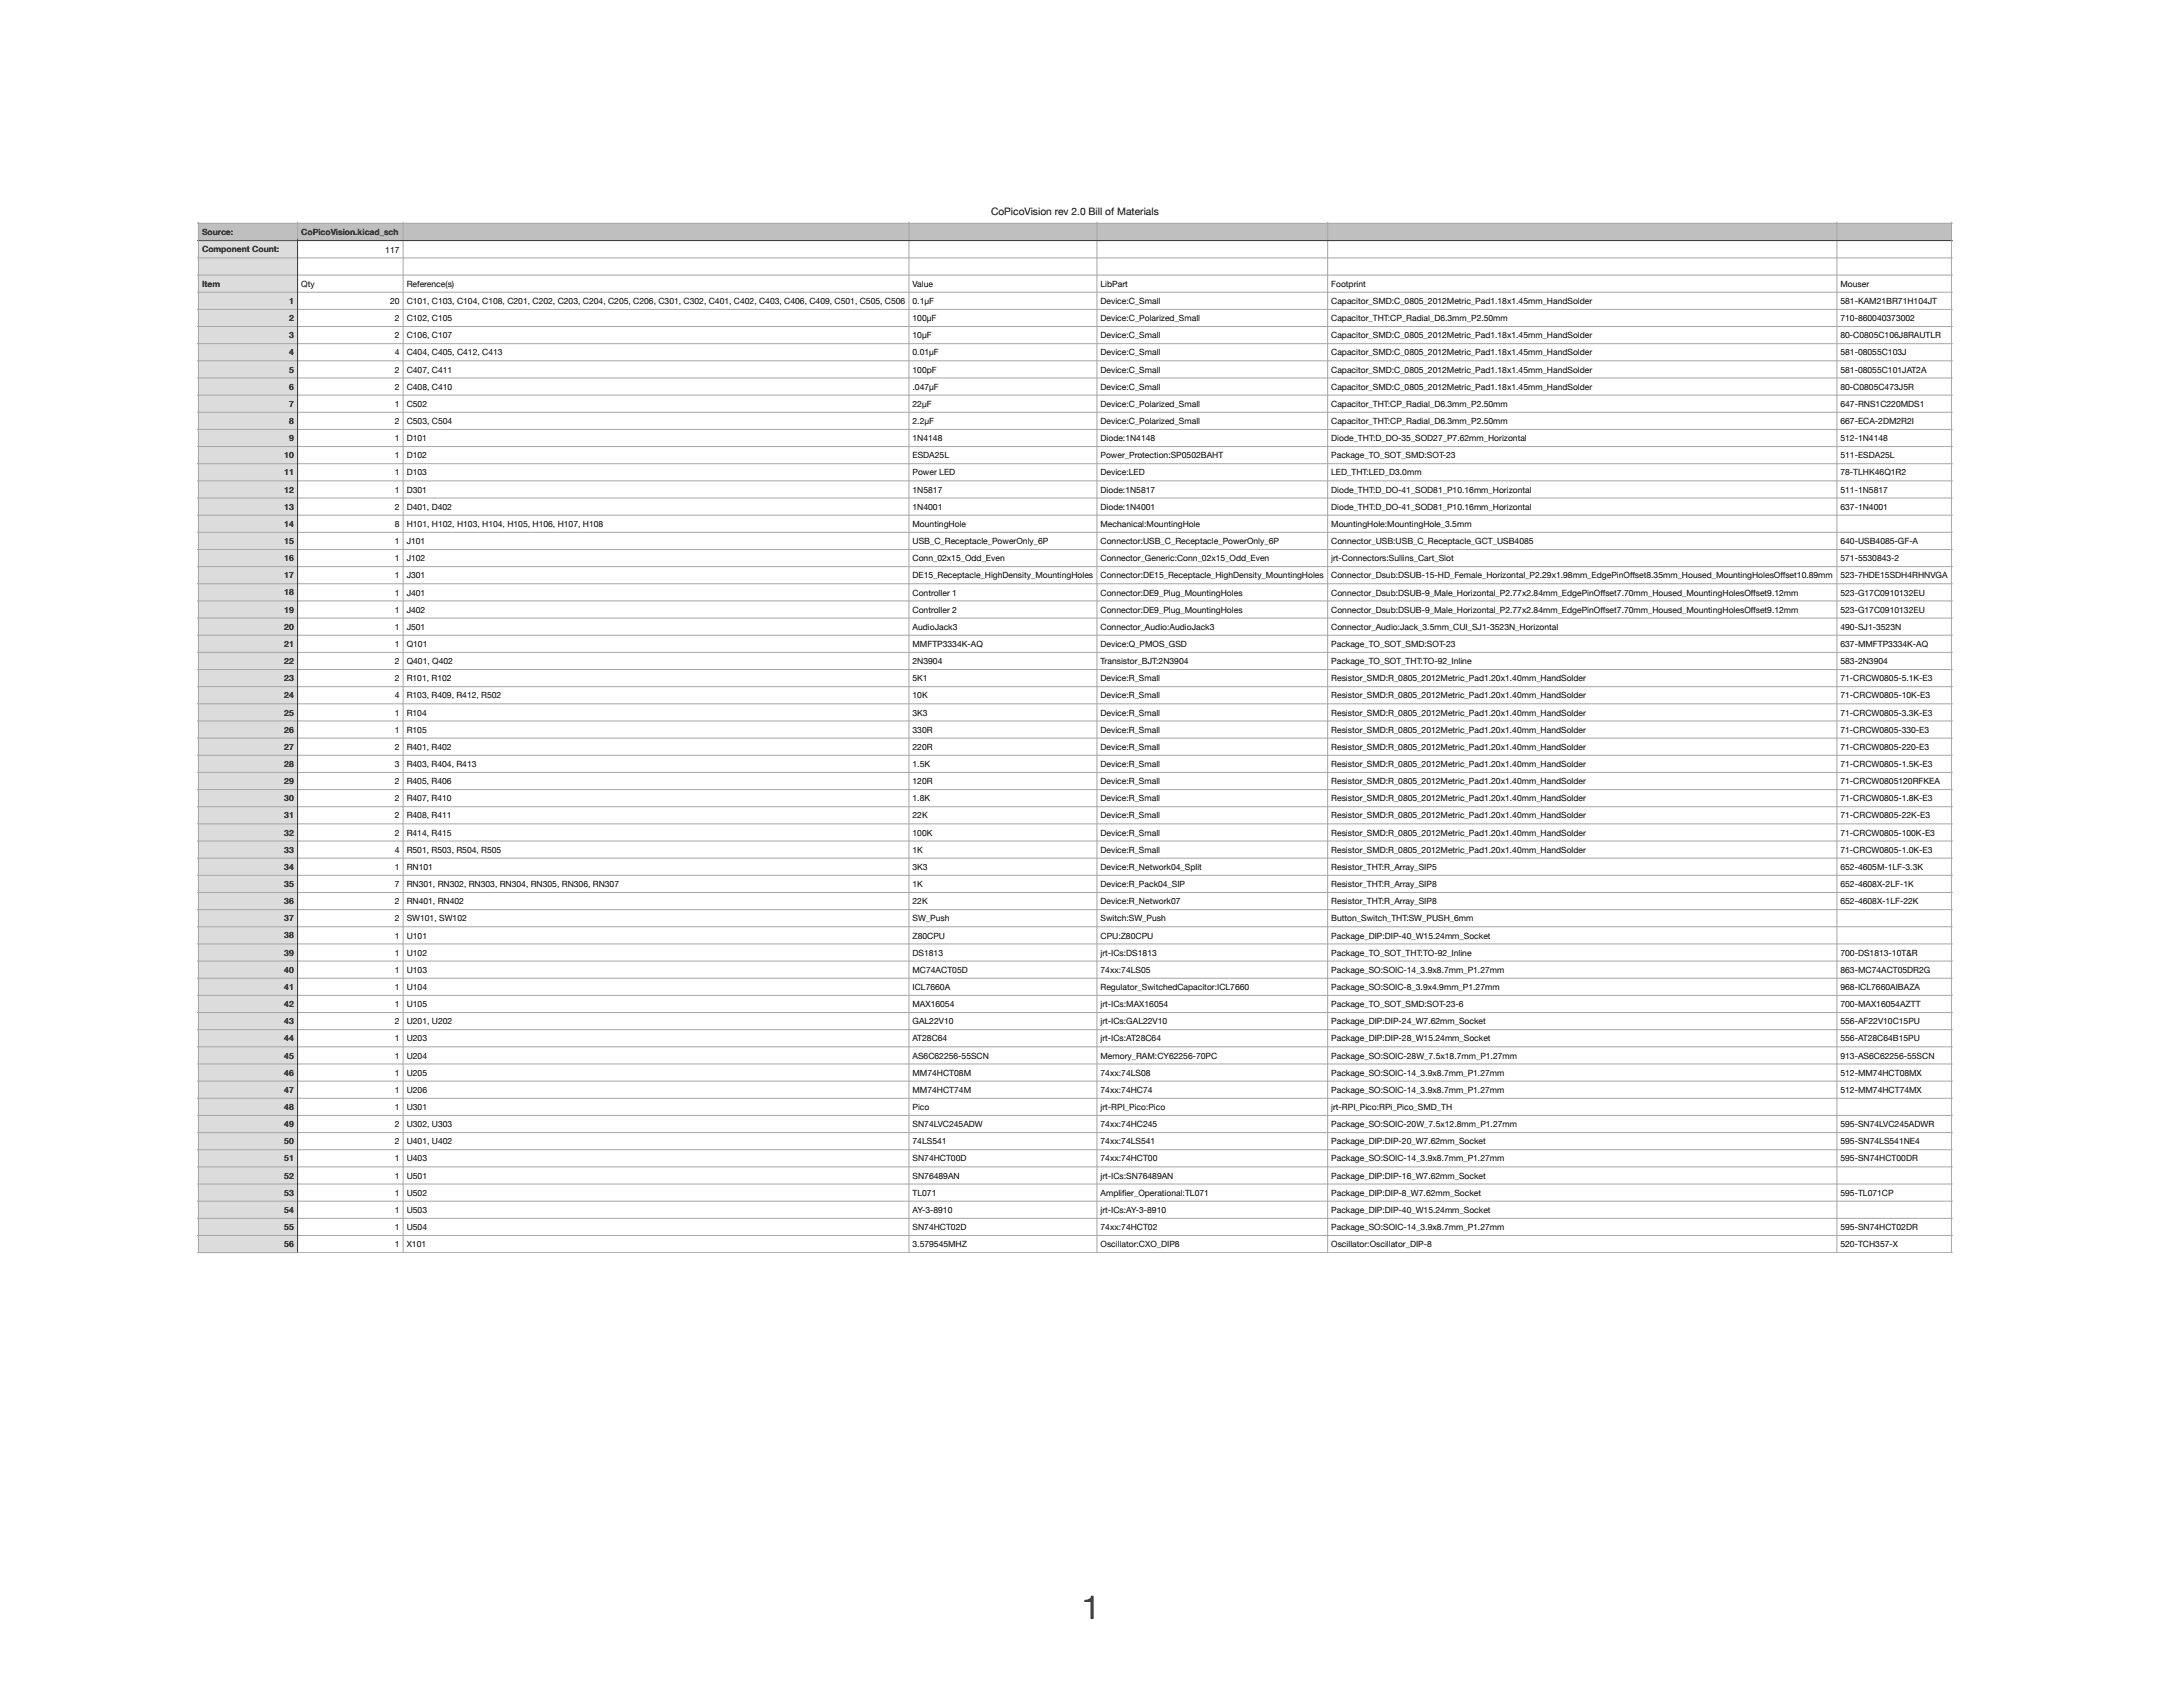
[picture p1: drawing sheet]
<svg xmlns="http://www.w3.org/2000/svg" width="279mm" height="216mm" viewBox="0 0 279 216" stroke-linecap="round" stroke-linejoin="round" font-family="sans-serif">
<defs><g id="words">
<text font-size="4.2" x="138.5" y="207.2">1</text>
<text font-size="1.3" x="126.8" y="27.5">CoPicoVision rev 2.0 Bill of Materials</text>
<g font-size="1.1">
<text x="25.9" y="30.1">Source:</text>
<text x="25.9" y="32.3">Component Count:</text>
<text x="38.5" y="30.1">CoPicoVision.kicad_sch</text>
<text x="49.3" y="32.3">117</text>
<text x="25.9" y="36.7">Item</text>
<text x="37" y="38.9">1</text>
<text x="37" y="41.1">2</text>
<text x="38.6" y="36.7">Qty</text>
<text x="49.9" y="38.9">20</text>
<text x="50.5" y="41.1">2</text>
<text x="52.1" y="36.7">Reference(s)</text>
<text x="52.1" y="38.9">C101, C103, C104, C108, C201, C202, C203, C204, C205, C206, C301, C302, C401, C402, C403, C406, C409, C501, C505, C506</text>
<text x="52.1" y="41.1">C102, C105</text>
<text x="116.8" y="36.7">Value</text>
<text x="116.8" y="38.9">0.1µF</text>
<text x="116.8" y="41.1">100µF</text>
<text x="140.9" y="36.7">LibPart</text>
<text x="140.9" y="38.9">Device:C_Small</text>
<text x="140.9" y="41.1">Device:C_Polarized_Small</text>
<text x="170.4" y="36.7">Footprint</text>
<text x="170.4" y="38.9">Capacitor_SMD:C_0805_2012Metric_Pad1.18x1.45mm_HandSolder</text>
<text x="170.4" y="41.1">Capacitor_THT:CP_Radial_D6.3mm_P2.50mm</text>
<text x="235.6" y="36.7">Mouser</text>
<text x="235.6" y="38.9">581-KAM21BR71H104JT</text>
<text x="235.6" y="41.1">710-860040373002</text>
<text x="37" y="43.3">3</text>
<text x="37" y="45.5">4</text>
<text x="37" y="47.7">5</text>
<text x="50.5" y="43.3">2</text>
<text x="50.5" y="45.5">4</text>
<text x="50.5" y="47.7">2</text>
<text x="52.1" y="43.3">C106, C107</text>
<text x="52.1" y="45.5">C404, C405, C412, C413</text>
<text x="52.1" y="47.7">C407, C411</text>
<text x="116.8" y="43.3">10µF</text>
<text x="116.8" y="45.5">0.01µF</text>
<text x="116.8" y="47.7">100pF</text>
<text x="140.9" y="43.3">Device:C_Small</text>
<text x="140.9" y="45.5">Device:C_Small</text>
<text x="140.9" y="47.7">Device:C_Small</text>
<text x="170.4" y="43.3">Capacitor_SMD:C_0805_2012Metric_Pad1.18x1.45mm_HandSolder</text>
<text x="170.4" y="45.5">Capacitor_SMD:C_0805_2012Metric_Pad1.18x1.45mm_HandSolder</text>
<text x="170.4" y="47.7">Capacitor_SMD:C_0805_2012Metric_Pad1.18x1.45mm_HandSolder</text>
<text x="235.6" y="43.3">80-C0805C106J8RAUTLR</text>
<text x="235.6" y="45.5">581-08055C103J</text>
<text x="235.6" y="47.7">581-08055C101JAT2A</text>
<text x="37" y="49.9">6</text>
<text x="37" y="52.1">7</text>
<text x="50.5" y="49.9">2</text>
<text x="50.5" y="52.1">1</text>
<text x="52.1" y="49.9">C408, C410</text>
<text x="52.1" y="52.1">C502</text>
<text x="116.8" y="49.9">.047µF</text>
<text x="116.8" y="52.1">22µF</text>
<text x="140.9" y="49.9">Device:C_Small</text>
<text x="140.9" y="52.1">Device:C_Polarized_Small</text>
<text x="170.4" y="49.9">Capacitor_SMD:C_0805_2012Metric_Pad1.18x1.45mm_HandSolder</text>
<text x="170.4" y="52.1">Capacitor_THT:CP_Radial_D6.3mm_P2.50mm</text>
<text x="235.6" y="49.9">80-C0805C473J5R</text>
<text x="235.6" y="52.1">647-RNS1C220MDS1</text>
<text x="36.4" y="58.7">10</text>
<text x="37" y="54.3">8</text>
<text x="37" y="56.5">9</text>
<text x="50.5" y="54.3">2</text>
<text x="50.5" y="56.5">1</text>
<text x="50.5" y="58.7">1</text>
<text x="52.1" y="54.3">C503, C504</text>
<text x="52.1" y="56.5">D101</text>
<text x="52.1" y="58.7">D102</text>
<text x="116.8" y="54.3">2.2µF</text>
<text x="116.8" y="56.5">1N4148</text>
<text x="116.8" y="58.7">ESDA25L</text>
<text x="140.9" y="54.3">Device:C_Polarized_Small</text>
<text x="140.9" y="56.5">Diode:1N4148</text>
<text x="140.9" y="58.7">Power_Protection:SP0502BAHT</text>
<text x="170.4" y="54.3">Capacitor_THT:CP_Radial_D6.3mm_P2.50mm</text>
<text x="170.4" y="56.5">Diode_THT:D_DO-35_SOD27_P7.62mm_Horizontal</text>
<text x="170.4" y="58.7">Package_TO_SOT_SMD:SOT-23</text>
<text x="235.6" y="54.3">667-ECA-2DM2R2I</text>
<text x="235.6" y="56.5">512-1N4148</text>
<text x="235.6" y="58.7">511-ESDA25L</text>
<text x="36.4" y="60.8">11</text>
<text x="36.4" y="63">12</text>
<text x="36.4" y="65.2">13</text>
<text x="50.5" y="60.9">1</text>
<text x="50.5" y="63">1</text>
<text x="50.5" y="65.2">2</text>
<text x="52.1" y="60.9">D103</text>
<text x="52.1" y="63">D301</text>
<text x="52.1" y="65.2">D401, D402</text>
<text x="116.8" y="60.9">Power LED</text>
<text x="116.8" y="63">1N5817</text>
<text x="116.8" y="65.2">1N4001</text>
<text x="140.9" y="60.9">Device:LED</text>
<text x="140.9" y="63">Diode:1N5817</text>
<text x="140.9" y="65.2">Diode:1N4001</text>
<text x="170.4" y="60.9">LED_THT:LED_D3.0mm</text>
<text x="170.4" y="63">Diode_THT:D_DO-41_SOD81_P10.16mm_Horizontal</text>
<text x="170.4" y="65.2">Diode_THT:D_DO-41_SOD81_P10.16mm_Horizontal</text>
<text x="235.6" y="60.9">78-TLHK46Q1R2</text>
<text x="235.6" y="63">511-1N5817</text>
<text x="235.6" y="65.2">637-1N4001</text>
<text x="36.4" y="67.4">14</text>
<text x="36.4" y="69.6">15</text>
<text x="36.4" y="71.8">16</text>
<text x="50.5" y="67.4">8</text>
<text x="50.5" y="69.6">1</text>
<text x="50.5" y="71.8">1</text>
<text x="52.1" y="67.4">H101, H102, H103, H104, H105, H106, H107, H108</text>
<text x="52.1" y="69.6">J101</text>
<text x="52.1" y="71.8">J102</text>
<text x="116.8" y="67.4">MountingHole</text>
<text x="116.8" y="69.6">USB_C_Receptacle_PowerOnly_6P</text>
<text x="116.8" y="71.8">Conn_02x15_Odd_Even</text>
<text x="140.9" y="67.4">Mechanical:MountingHole</text>
<text x="140.9" y="69.6">Connector:USB_C_Receptacle_PowerOnly_6P</text>
<text x="140.9" y="71.8">Connector_Generic:Conn_02x15_Odd_Even</text>
<text x="170.4" y="67.4">MountingHole:MountingHole_3.5mm</text>
<text x="170.4" y="69.6">Connector_USB:USB_C_Receptacle_GCT_USB4085</text>
<text x="170.4" y="71.8">jrt-Connectors:Sullins_Cart_Slot</text>
<text x="235.6" y="69.6">640-USB4085-GF-A</text>
<text x="235.6" y="71.8">571-5530843-2</text>
<text x="36.4" y="74">17</text>
<text x="36.4" y="76.2">18</text>
<text x="50.5" y="74">1</text>
<text x="50.5" y="76.2">1</text>
<text x="52.1" y="74">J301</text>
<text x="52.1" y="76.2">J401</text>
<text x="116.8" y="74">DE15_Receptacle_HighDensity_MountingHoles</text>
<text x="116.8" y="76.2">Controller 1</text>
<text x="140.9" y="74">Connector:DE15_Receptacle_HighDensity_MountingHoles</text>
<text x="140.9" y="76.2">Connector:DE9_Plug_MountingHoles</text>
<text x="170.4" y="74">Connector_Dsub:DSUB-15-HD_Female_Horizontal_P2.29x1.98mm_EdgePinOff set8.35mm_Housed_MountingHolesOff set10.89mm</text>
<text x="170.4" y="76.2">Connector_Dsub:DSUB-9_Male_Horizontal_P2.77x2.84mm_EdgePinOff set7.70mm_Housed_MountingHolesOff set9.12mm</text>
<text x="235.6" y="74">523-7HDE15SDH4RHNVGA</text>
<text x="235.6" y="76.2">523-G17C0910132EU</text>
<text x="36.4" y="78.4">19</text>
<text x="36.4" y="80.6">20</text>
<text x="36.4" y="82.8">21</text>
<text x="50.5" y="78.4">1</text>
<text x="50.5" y="80.6">1</text>
<text x="50.5" y="82.8">1</text>
<text x="52.1" y="78.4">J402</text>
<text x="52.1" y="80.6">J501</text>
<text x="52.1" y="82.8">Q101</text>
<text x="116.8" y="78.4">Controller 2</text>
<text x="116.8" y="80.6">AudioJack3</text>
<text x="116.8" y="82.8">MMFTP3334K-AQ</text>
<text x="140.9" y="78.4">Connector:DE9_Plug_MountingHoles</text>
<text x="140.9" y="80.6">Connector_Audio:AudioJack3</text>
<text x="140.9" y="82.8">Device:Q_PMOS_GSD</text>
<text x="170.4" y="78.4">Connector_Dsub:DSUB-9_Male_Horizontal_P2.77x2.84mm_EdgePinOff set7.70mm_Housed_MountingHolesOff set9.12mm</text>
<text x="170.4" y="80.6">Connector_Audio:Jack_3.5mm_CUI_SJ1-3523N_Horizontal</text>
<text x="170.4" y="82.8">Package_TO_SOT_SMD:SOT-23</text>
<text x="235.6" y="78.4">523-G17C0910132EU</text>
<text x="235.6" y="80.6">490-SJ1-3523N</text>
<text x="235.6" y="82.8">637-MMFTP3334K-AQ</text>
<text x="36.4" y="85">22</text>
<text x="36.4" y="87.2">23</text>
<text x="36.4" y="89.4">24</text>
<text x="50.5" y="85">2</text>
<text x="50.5" y="87.2">2</text>
<text x="50.5" y="89.4">4</text>
<text x="52.1" y="85">Q401, Q402</text>
<text x="52.1" y="87.2">R101, R102</text>
<text x="52.1" y="89.4">R103, R409, R412, R502</text>
<text x="116.8" y="85">2N3904</text>
<text x="116.8" y="87.2">5K1</text>
<text x="116.8" y="89.4">10K</text>
<text x="140.9" y="85">Transistor_BJT:2N3904</text>
<text x="140.9" y="87.2">Device:R_Small</text>
<text x="140.9" y="89.4">Device:R_Small</text>
<text x="170.4" y="85">Package_TO_SOT_THT:TO-92_Inline</text>
<text x="170.4" y="87.2">Resistor_SMD:R_0805_2012Metric_Pad1.20x1.40mm_HandSolder</text>
<text x="170.4" y="89.4">Resistor_SMD:R_0805_2012Metric_Pad1.20x1.40mm_HandSolder</text>
<text x="235.6" y="85">583-2N3904</text>
<text x="235.6" y="87.2">71-CRCW0805-5.1K-E3</text>
<text x="235.6" y="89.4">71-CRCW0805-10K-E3</text>
<text x="36.4" y="91.6">25</text>
<text x="36.4" y="93.8">26</text>
<text x="36.4" y="96">27</text>
<text x="50.5" y="91.6">1</text>
<text x="50.5" y="93.8">1</text>
<text x="50.5" y="96">2</text>
<text x="52.1" y="91.6">R104</text>
<text x="52.1" y="93.8">R105</text>
<text x="52.1" y="96">R401, R402</text>
<text x="116.8" y="91.6">3K3</text>
<text x="116.8" y="93.8">330R</text>
<text x="116.8" y="96">220R</text>
<text x="140.9" y="91.6">Device:R_Small</text>
<text x="140.9" y="93.8">Device:R_Small</text>
<text x="140.9" y="96">Device:R_Small</text>
<text x="170.4" y="91.6">Resistor_SMD:R_0805_2012Metric_Pad1.20x1.40mm_HandSolder</text>
<text x="170.4" y="93.8">Resistor_SMD:R_0805_2012Metric_Pad1.20x1.40mm_HandSolder</text>
<text x="170.4" y="96">Resistor_SMD:R_0805_2012Metric_Pad1.20x1.40mm_HandSolder</text>
<text x="235.6" y="91.6">71-CRCW0805-3.3K-E3</text>
<text x="235.6" y="93.8">71-CRCW0805-330-E3</text>
<text x="235.6" y="96">71-CRCW0805-220-E3</text>
<text x="36.4" y="98.2">28</text>
<text x="36.4" y="100.4">29</text>
<text x="50.5" y="98.2">3</text>
<text x="50.5" y="100.4">2</text>
<text x="52.1" y="98.2">R403, R404, R413</text>
<text x="52.1" y="100.4">R405, R406</text>
<text x="116.8" y="98.2">1.5K</text>
<text x="116.8" y="100.4">120R</text>
<text x="140.9" y="98.2">Device:R_Small</text>
<text x="140.9" y="100.4">Device:R_Small</text>
<text x="170.4" y="98.2">Resistor_SMD:R_0805_2012Metric_Pad1.20x1.40mm_HandSolder</text>
<text x="170.4" y="100.4">Resistor_SMD:R_0805_2012Metric_Pad1.20x1.40mm_HandSolder</text>
<text x="235.6" y="98.2">71-CRCW0805-1.5K-E3</text>
<text x="235.6" y="100.4">71-CRCW0805120RFKEA</text>
<text x="36.4" y="102.5">30</text>
<text x="36.4" y="104.7">31</text>
<text x="36.4" y="106.9">32</text>
<text x="50.5" y="102.6">2</text>
<text x="50.5" y="104.7">2</text>
<text x="50.5" y="106.9">2</text>
<text x="52.1" y="102.6">R407, R410</text>
<text x="52.1" y="104.7">R408, R411</text>
<text x="52.1" y="106.9">R414, R415</text>
<text x="116.8" y="102.6">1.8K</text>
<text x="116.8" y="104.7">22K</text>
<text x="116.8" y="106.9">100K</text>
<text x="140.9" y="102.6">Device:R_Small</text>
<text x="140.9" y="104.7">Device:R_Small</text>
<text x="140.9" y="106.9">Device:R_Small</text>
<text x="170.4" y="102.6">Resistor_SMD:R_0805_2012Metric_Pad1.20x1.40mm_HandSolder</text>
<text x="170.4" y="104.7">Resistor_SMD:R_0805_2012Metric_Pad1.20x1.40mm_HandSolder</text>
<text x="170.4" y="106.9">Resistor_SMD:R_0805_2012Metric_Pad1.20x1.40mm_HandSolder</text>
<text x="235.6" y="102.6">71-CRCW0805-1.8K-E3</text>
<text x="235.6" y="104.7">71-CRCW0805-22K-E3</text>
<text x="235.6" y="106.9">71-CRCW0805-100K-E3</text>
<text x="36.4" y="109.1">33</text>
<text x="36.4" y="111.3">34</text>
<text x="36.4" y="113.5">35</text>
<text x="50.5" y="109.1">4</text>
<text x="50.5" y="111.3">1</text>
<text x="50.5" y="113.5">7</text>
<text x="52.1" y="109.1">R501, R503, R504, R505</text>
<text x="52.1" y="111.3">RN101</text>
<text x="52.1" y="113.5">RN301, RN302, RN303, RN304, RN305, RN306, RN307</text>
<text x="116.8" y="109.1">1K</text>
<text x="116.8" y="111.3">3K3</text>
<text x="116.8" y="113.5">1K</text>
<text x="140.9" y="109.1">Device:R_Small</text>
<text x="140.9" y="111.3">Device:R_Network04_Split</text>
<text x="140.9" y="113.5">Device:R_Pack04_SIP</text>
<text x="170.4" y="109.1">Resistor_SMD:R_0805_2012Metric_Pad1.20x1.40mm_HandSolder</text>
<text x="170.4" y="111.3">Resistor_THT:R_Array_SIP5</text>
<text x="170.4" y="113.5">Resistor_THT:R_Array_SIP8</text>
<text x="235.6" y="109.1">71-CRCW0805-1.0K-E3</text>
<text x="235.6" y="111.3">652-4605M-1LF-3.3K</text>
<text x="235.6" y="113.5">652-4608X-2LF-1K</text>
<text x="36.4" y="115.7">36</text>
<text x="36.4" y="117.9">37</text>
<text x="50.5" y="115.7">2</text>
<text x="50.5" y="117.9">2</text>
<text x="52.1" y="115.7">RN401, RN402</text>
<text x="52.1" y="117.9">SW101, SW102</text>
<text x="116.8" y="115.7">22K</text>
<text x="116.8" y="117.9">SW_Push</text>
<text x="140.9" y="115.7">Device:R_Network07</text>
<text x="140.9" y="117.9">Switch:SW_Push</text>
<text x="170.4" y="115.7">Resistor_THT:R_Array_SIP8</text>
<text x="170.4" y="117.9">Button_Switch_THT:SW_PUSH_6mm</text>
<text x="235.6" y="115.7">652-4608X-1LF-22K</text>
<text x="36.4" y="120.1">38</text>
<text x="36.4" y="122.3">39</text>
<text x="36.4" y="124.5">40</text>
<text x="50.5" y="120.1">1</text>
<text x="50.5" y="122.3">1</text>
<text x="50.5" y="124.5">1</text>
<text x="52.1" y="120.1">U101</text>
<text x="52.1" y="122.3">U102</text>
<text x="52.1" y="124.5">U103</text>
<text x="116.8" y="120.1">Z80CPU</text>
<text x="116.8" y="122.3">DS1813</text>
<text x="116.8" y="124.5">MC74ACT05D</text>
<text x="140.9" y="120.1">CPU:Z80CPU</text>
<text x="140.9" y="122.3">jrt-ICs:DS1813</text>
<text x="140.9" y="124.5">74xx:74LS05</text>
<text x="170.4" y="120.1">Package_DIP:DIP-40_W15.24mm_Socket</text>
<text x="170.4" y="122.3">Package_TO_SOT_THT:TO-92_Inline</text>
<text x="170.4" y="124.5">Package_SO:SOIC-14_3.9x8.7mm_P1.27mm</text>
<text x="235.6" y="122.3">700-DS1813-10T&amp;R</text>
<text x="235.6" y="124.5">863-MC74ACT05DR2G</text>
<text x="36.4" y="126.7">41</text>
<text x="36.4" y="128.9">42</text>
<text x="36.4" y="131.1">43</text>
<text x="50.5" y="126.7">1</text>
<text x="50.5" y="128.9">1</text>
<text x="50.5" y="131.1">2</text>
<text x="52.1" y="126.7">U104</text>
<text x="52.1" y="128.9">U105</text>
<text x="52.1" y="131.1">U201, U202</text>
<text x="116.8" y="126.7">ICL7660A</text>
<text x="116.8" y="128.9">MAX16054</text>
<text x="116.8" y="131.1">GAL22V10</text>
<text x="140.9" y="126.7">Regulator_SwitchedCapacitor:ICL7660</text>
<text x="140.9" y="128.9">jrt-ICs:MAX16054</text>
<text x="140.9" y="131.1">jrt-ICs:GAL22V10</text>
<text x="170.4" y="126.7">Package_SO:SOIC-8_3.9x4.9mm_P1.27mm</text>
<text x="170.4" y="128.9">Package_TO_SOT_SMD:SOT-23-6</text>
<text x="170.4" y="131.1">Package_DIP:DIP-24_W7.62mm_Socket</text>
<text x="235.6" y="126.7">968-ICL7660AIBAZA</text>
<text x="235.6" y="128.9">700-MAX16054AZTT</text>
<text x="235.6" y="131.1">556-AF22V10C15PU</text>
<text x="36.4" y="133.3">44</text>
<text x="36.4" y="135.5">45</text>
<text x="36.4" y="137.7">46</text>
<text x="50.5" y="133.3">1</text>
<text x="50.5" y="135.5">1</text>
<text x="50.5" y="137.7">1</text>
<text x="52.1" y="133.3">U203</text>
<text x="52.1" y="135.5">U204</text>
<text x="52.1" y="137.7">U205</text>
<text x="116.8" y="133.3">AT28C64</text>
<text x="116.8" y="135.5">AS6C62256-55SCN</text>
<text x="116.8" y="137.7">MM74HCT08M</text>
<text x="140.9" y="133.3">jrt-ICs:AT28C64</text>
<text x="140.9" y="135.5">Memory_RAM:CY62256-70PC</text>
<text x="140.9" y="137.7">74xx:74LS08</text>
<text x="170.4" y="133.3">Package_DIP:DIP-28_W15.24mm_Socket</text>
<text x="170.4" y="135.5">Package_SO:SOIC-28W_7.5x18.7mm_P1.27mm</text>
<text x="170.4" y="137.7">Package_SO:SOIC-14_3.9x8.7mm_P1.27mm</text>
<text x="235.6" y="133.3">556-AT28C64B15PU</text>
<text x="235.6" y="135.5">913-AS6C62256-55SCN</text>
<text x="235.6" y="137.7">512-MM74HCT08MX</text>
<text x="36.4" y="139.9">47</text>
<text x="36.4" y="142.1">48</text>
<text x="50.5" y="139.9">1</text>
<text x="50.5" y="142.1">1</text>
<text x="52.1" y="139.9">U206</text>
<text x="52.1" y="142.1">U301</text>
<text x="116.8" y="139.9">MM74HCT74M</text>
<text x="116.8" y="142.1">Pico</text>
<text x="140.9" y="139.9">74xx:74HC74</text>
<text x="140.9" y="142.1">jrt-RPI_Pico:Pico</text>
<text x="170.4" y="139.9">Package_SO:SOIC-14_3.9x8.7mm_P1.27mm</text>
<text x="170.4" y="142.1">jrt-RPI_Pico:RPi_Pico_SMD_TH</text>
<text x="235.6" y="139.9">512-MM74HCT74MX</text>
<text x="36.4" y="144.3">49</text>
<text x="36.4" y="146.4">50</text>
<text x="36.4" y="148.6">51</text>
<text x="50.5" y="144.3">2</text>
<text x="50.5" y="146.5">2</text>
<text x="50.5" y="148.6">1</text>
<text x="52.1" y="144.3">U302, U303</text>
<text x="52.1" y="146.5">U401, U402</text>
<text x="52.1" y="148.6">U403</text>
<text x="116.8" y="144.3">SN74LVC245ADW</text>
<text x="116.8" y="146.5">74LS541</text>
<text x="116.8" y="148.6">SN74HCT00D</text>
<text x="140.9" y="144.3">74xx:74HC245</text>
<text x="140.9" y="146.5">74xx:74LS541</text>
<text x="140.9" y="148.6">74xx:74HCT00</text>
<text x="170.4" y="144.3">Package_SO:SOIC-20W_7.5x12.8mm_P1.27mm</text>
<text x="170.4" y="146.5">Package_DIP:DIP-20_W7.62mm_Socket</text>
<text x="170.4" y="148.6">Package_SO:SOIC-14_3.9x8.7mm_P1.27mm</text>
<text x="235.6" y="144.3">595-SN74LVC245ADWR</text>
<text x="235.6" y="146.5">595-SN74LS541NE4</text>
<text x="235.6" y="148.6">595-SN74HCT00DR</text>
<text x="36.4" y="150.8">52</text>
<text x="36.4" y="153">53</text>
<text x="36.4" y="155.2">54</text>
<text x="50.5" y="150.8">1</text>
<text x="50.5" y="153">1</text>
<text x="50.5" y="155.2">1</text>
<text x="52.1" y="150.8">U501</text>
<text x="52.1" y="153">U502</text>
<text x="52.1" y="155.2">U503</text>
<text x="116.8" y="150.8">SN76489AN</text>
<text x="116.8" y="153">TL071</text>
<text x="116.8" y="155.2">AY-3-8910</text>
<text x="140.9" y="150.8">jrt-ICs:SN76489AN</text>
<text x="140.9" y="153">Amplifi er_Operational:TL071</text>
<text x="140.9" y="155.2">jrt-ICs:AY-3-8910</text>
<text x="170.4" y="150.8">Package_DIP:DIP-16_W7.62mm_Socket</text>
<text x="170.4" y="153">Package_DIP:DIP-8_W7.62mm_Socket</text>
<text x="170.4" y="155.2">Package_DIP:DIP-40_W15.24mm_Socket</text>
<text x="235.6" y="153">595-TL071CP</text>
<text x="36.4" y="157.4">55</text>
<text x="36.4" y="159.6">56</text>
<text x="50.5" y="157.4">1</text>
<text x="50.5" y="159.6">1</text>
<text x="52.1" y="157.4">U504</text>
<text x="52.1" y="159.6">X101</text>
<text x="116.8" y="157.4">SN74HCT02D</text>
<text x="116.8" y="159.6">3.579545MHZ</text>
<text x="140.9" y="157.4">74xx:74HCT02</text>
<text x="140.9" y="159.6">Oscillator:CXO_DIP8</text>
<text x="170.4" y="157.4">Package_SO:SOIC-14_3.9x8.7mm_P1.27mm</text>
<text x="170.4" y="159.6">Oscillator:Oscillator_DIP-8</text>
<text x="235.6" y="157.4">595-SN74HCT02DR</text>
<text x="235.6" y="159.6">520-TCH357-X</text>
</g>
</g></defs>
<g fill="#bec0bf">
<path d="M25.4 28.6h12.7v2.2h-12.7z"/>
<path d="M38.1 28.6h13.5v2.2h-13.5z"/>
<path d="M51.6 28.6h64.7v2.2h-64.7z"/>
<path d="M116.3 28.6h24.1v2.2h-24.1z"/>
<path d="M140.4 28.6h29.5v2.2h-29.5z"/>
<path d="M169.9 28.6h65.2v2.2h-65.2z"/>
<path d="M235.1 28.6h14.7v2.2h-14.7z"/>
</g>
<g fill="#dcdcdc">
<path d="M25.4 30.8h12.7v2.2h-12.7z"/>
<path d="M25.4 33h12.7v2.2h-12.7z"/>
<path d="M25.4 35.2h12.7v2.2h-12.7z"/>
<path d="M25.4 37.4h12.7v2.2h-12.7z"/>
<path d="M25.4 39.6h12.7v2.2h-12.7z"/>
<path d="M25.4 41.8h12.7v2.2h-12.7z"/>
<path d="M25.4 44h12.7v2.2h-12.7z"/>
<path d="M25.4 46.2h12.7v2.2h-12.7z"/>
<path d="M25.4 48.4h12.7v2.2h-12.7z"/>
<path d="M25.4 50.6h12.7v2.2h-12.7z"/>
<path d="M25.4 52.8h12.7v2.2h-12.7z"/>
<path d="M25.4 55h12.7v2.2h-12.7z"/>
<path d="M25.4 57.2h12.7v2.1h-12.7z"/>
<path d="M25.4 59.3h12.7v2.2h-12.7z"/>
<path d="M25.4 61.5h12.7v2.2h-12.7z"/>
<path d="M25.4 63.7h12.7v2.2h-12.7z"/>
<path d="M25.4 65.9h12.7v2.2h-12.7z"/>
<path d="M25.4 68.1h12.7v2.2h-12.7z"/>
<path d="M25.4 70.3h12.7v2.2h-12.7z"/>
<path d="M25.4 72.5h12.7v2.2h-12.7z"/>
<path d="M25.4 74.7h12.7v2.2h-12.7z"/>
<path d="M25.4 76.9h12.7v2.2h-12.7z"/>
<path d="M25.4 79.1h12.7v2.2h-12.7z"/>
<path d="M25.4 81.3h12.7v2.2h-12.7z"/>
<path d="M25.4 83.5h12.7v2.2h-12.7z"/>
<path d="M25.4 85.7h12.7v2.2h-12.7z"/>
<path d="M25.4 87.9h12.7v2.2h-12.7z"/>
<path d="M25.4 90.1h12.7v2.2h-12.7z"/>
<path d="M25.4 92.3h12.7v2.2h-12.7z"/>
<path d="M25.4 94.5h12.7v2.2h-12.7z"/>
<path d="M25.4 96.7h12.7v2.2h-12.7z"/>
<path d="M25.4 98.9h12.7v2.1h-12.7z"/>
<path d="M25.4 101h12.7v2.2h-12.7z"/>
<path d="M25.4 103.2h12.7v2.2h-12.7z"/>
<path d="M25.4 105.4h12.7v2.2h-12.7z"/>
<path d="M25.4 107.6h12.7v2.2h-12.7z"/>
<path d="M25.4 109.8h12.7v2.2h-12.7z"/>
<path d="M25.4 112h12.7v2.2h-12.7z"/>
<path d="M25.4 114.2h12.7v2.2h-12.7z"/>
<path d="M25.4 116.4h12.7v2.2h-12.7z"/>
<path d="M25.4 118.6h12.7v2.2h-12.7z"/>
<path d="M25.4 120.8h12.7v2.2h-12.7z"/>
<path d="M25.4 123h12.7v2.2h-12.7z"/>
<path d="M25.4 125.2h12.7v2.2h-12.7z"/>
<path d="M25.4 127.4h12.7v2.2h-12.7z"/>
<path d="M25.4 129.6h12.7v2.2h-12.7z"/>
<path d="M25.4 131.8h12.7v2.2h-12.7z"/>
<path d="M25.4 134h12.7v2.2h-12.7z"/>
<path d="M25.4 136.2h12.7v2.2h-12.7z"/>
<path d="M25.4 138.4h12.7v2.2h-12.7z"/>
<path d="M25.4 140.6h12.7v2.2h-12.7z"/>
<path d="M25.4 142.8h12.7v2.1h-12.7z"/>
<path d="M25.4 144.9h12.7v2.2h-12.7z"/>
<path d="M25.4 147.1h12.7v2.2h-12.7z"/>
<path d="M25.4 149.3h12.7v2.2h-12.7z"/>
<path d="M25.4 151.5h12.7v2.2h-12.7z"/>
<path d="M25.4 153.7h12.7v2.2h-12.7z"/>
<path d="M25.4 155.9h12.7v2.2h-12.7z"/>
<path d="M25.4 158.1h12.7v2.2h-12.7z"/>
</g>
<g fill="none" stroke="#a6a6a6" stroke-width=".13">
<path d="M25.2 33h224.7M25.2 35.2h224.7M25.2 37.4h224.7M25.2 39.6h224.7M25.2 28.6h224.7M25.4 28.4v132M38.1 28.4v2.2M51.6 28.4v132M116.3 28.4v132M140.4 28.4v132M169.9 28.4v132M235.1 28.4v132"/>
<path d="M249.8 28.4v132M25.2 41.8h224.7M25.2 44h224.7M25.2 46.2h224.7M25.2 48.4h224.7M25.2 50.6h224.7M25.2 52.8h224.7M25.2 55h224.7M25.2 57.2h224.7M25.2 59.3h224.7M25.2 61.5h224.7M25.2 63.7h224.7"/>
<path d="M25.2 65.9h224.7M25.2 68.1h224.7M25.2 70.3h224.7M25.2 72.5h224.7M25.2 74.7h224.7M25.2 76.9h224.7M25.2 79.1h224.7M25.2 81.3h224.7M25.2 83.5h224.7M25.2 85.7h224.7M25.2 87.9h224.7M25.2 90.1h224.7"/>
<path d="M25.2 92.3h224.7M25.2 94.5h224.7M25.2 96.7h224.7M25.2 98.9h224.7M25.2 101h224.7M25.2 103.2h224.7M25.2 105.4h224.7M25.2 107.6h224.7M25.2 109.8h224.7M25.2 112h224.7M25.2 114.2h224.7M25.2 116.4h224.7"/>
<path d="M25.2 118.6h224.7M25.2 120.8h224.7M25.2 123h224.7M25.2 125.2h224.7M25.2 127.4h224.7M25.2 129.6h224.7M25.2 131.8h224.7M25.2 134h224.7M25.2 136.2h224.7M25.2 138.4h224.7M25.2 140.6h224.7M25.2 142.8h224.7"/>
<path d="M25.2 144.9h224.7M25.2 147.1h224.7M25.2 149.3h224.7M25.2 151.5h224.7M25.2 153.7h224.7M25.2 155.9h224.7M25.2 158.1h224.7M25.2 160.3h224.7"/>
</g>
<path d="M25.2 30.8h224.7M38.1 30.6v129.8" fill="none" stroke="#404040" stroke-width=".13"/>
<use href="#words"/>
</svg>
